Omron CX-Programmer project CJSCsp00 (CX-Programmer 3.01)

# PLC CJ_PC1: CJ1G-H CPU44

## Global symbols (name address type ; comment)
1509.11 BOOL  ; Sequence End
1509.15 BOOL  ; Busy of Macro
A202.00 BOOL  ; Ready of Logical Port0
A392.06 BOOL  ; Sys. Receive Complete
D100 CHANNEL  ; Axis Number
D101 CHANNEL  ; Function Code
D102 CHANNEL  ; Oｅｒａｎｄ L
D103 CHANNEL  ; Operand H
D105 CHANNEL  ; Stat. Res. Axis Number
D106 CHANNEL  ; PI PO
D107 CHANNEL  ; STAT ALRM
D120 CHANNEL  ; Pos. Res. Axis Number
D121 CHANNEL  ; Vel. Res. Axis Number
D122 CHANNEL  ; Read Res. Axis Number
D130 CHANNEL  ; Position L
D131 CHANNEL  ; Position H
D139 CHANNEL  ; Bytes ｔo Send
D159 CHANNEL  ; Bytes to Receive
D178 CHANNEL  ; Temp Register
D180 CHANNEL  ; Communication Parameter
D181 CHANNEL  ; 9600bps
D182 CHANNEL  ; Delay0
D184 CHANNEL  ; StartCode STX StopCode ETX
D185 CHANNEL  ; 14char/block
D188 CHANNEL  ; Half Duplex
D189 CHANNEL  ; Max Data Size
T0015 BOOL  ; Communicatin Idle Timer
W40.00 BOOL  ; Command Send Request
W40.01 BOOL  ; Communication is Executing
W40.02 BOOL  ; Res. Checksum Error
W40.05 BOOL  ; Responce Data OK
W40.07 BOOL  ; Command Send Req Pulse
W41.00 BOOL  ; Receive Complete
W41.01 BOOL  ; Sequence Normal End

## Program CJCSsp00 (cyclic task 0)

### Section ｾｸｼｮﾝ1

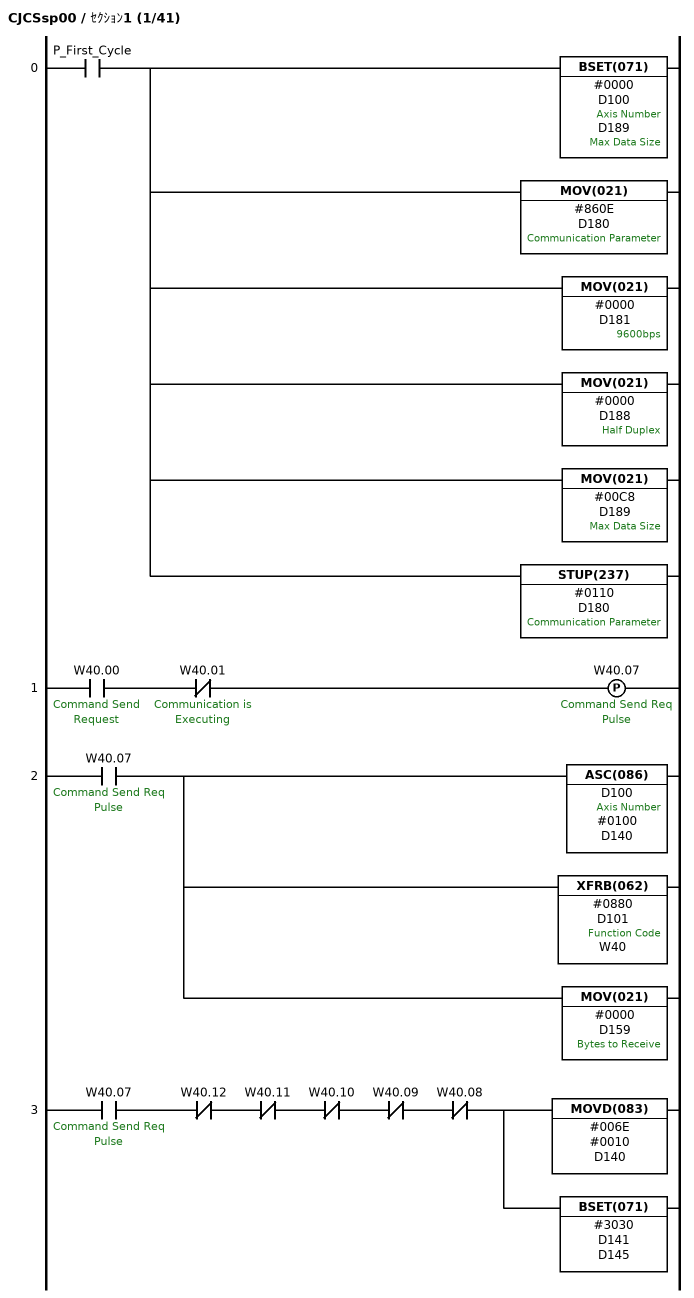
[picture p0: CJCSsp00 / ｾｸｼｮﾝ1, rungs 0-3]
; rung 0
LD P_First_Cycle
BSET(071) #0000 D100 D189  ; Axis Number, Max Data Size
MOV(021) #860E D180  ; Communication Parameter
MOV(021) #0000 D181  ; 9600bps
MOV(021) #0000 D188  ; Half Duplex
MOV(021) #00C8 D189  ; Max Data Size
STUP(237) #0110 D180  ; Communication Parameter
; rung 1
LD W40.00  ; Command Send Request
ANDNOT W40.01  ; Communication is Executing
DIFU(013) W40.07  ; Command Send Req Pulse
; rung 2
LD W40.07  ; Command Send Req Pulse
ASC(086) D100 #0100 D140  ; Axis Number
XFRB(062) #0880 D101 W40  ; Function Code
MOV(021) #0000 D159  ; Bytes to Receive
; rung 3
LD W40.07  ; Command Send Req Pulse
ANDNOT W40.12
ANDNOT W40.11
ANDNOT W40.10
ANDNOT W40.09
ANDNOT W40.08
MOVD(083) #006E #0010 D140
BSET(071) #3030 D141 D145

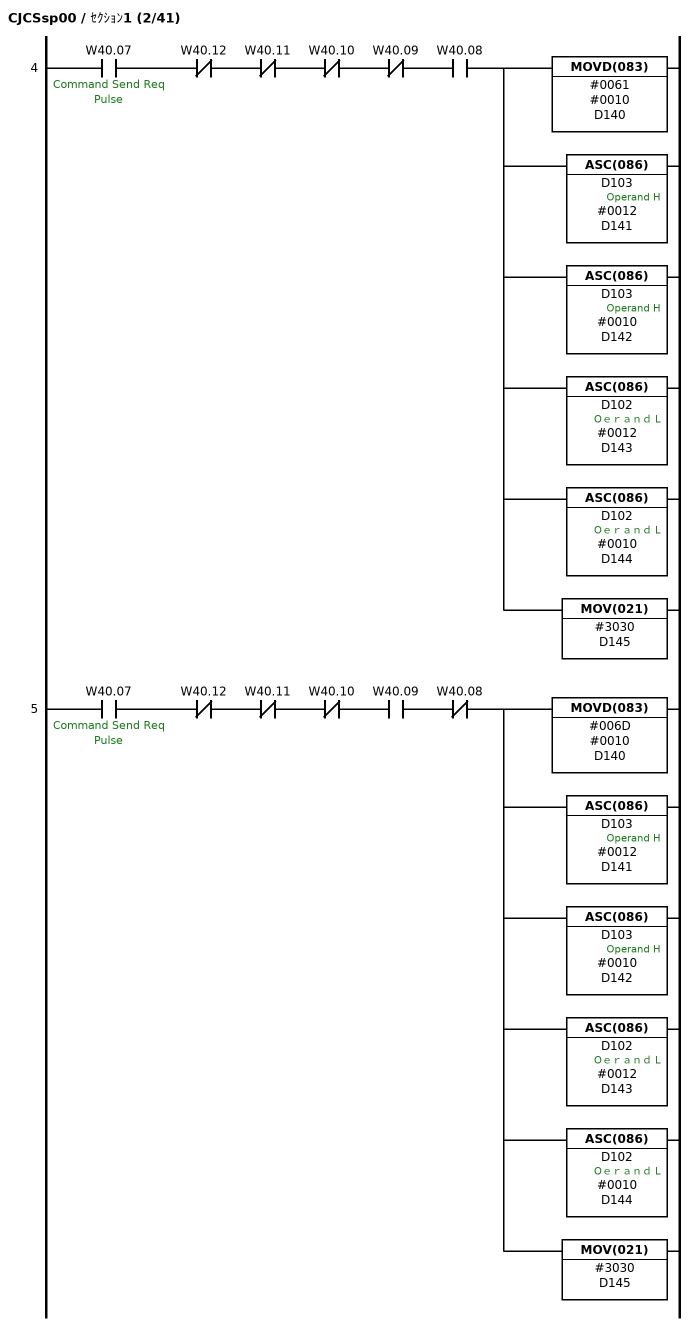
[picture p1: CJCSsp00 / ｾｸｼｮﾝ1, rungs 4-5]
; rung 4
LD W40.07  ; Command Send Req Pulse
ANDNOT W40.12
ANDNOT W40.11
ANDNOT W40.10
ANDNOT W40.09
AND W40.08
MOVD(083) #0061 #0010 D140
ASC(086) D103 #0012 D141  ; Operand H
ASC(086) D103 #0010 D142  ; Operand H
ASC(086) D102 #0012 D143  ; Oｅｒａｎｄ L
ASC(086) D102 #0010 D144  ; Oｅｒａｎｄ L
MOV(021) #3030 D145
; rung 5
LD W40.07  ; Command Send Req Pulse
ANDNOT W40.12
ANDNOT W40.11
ANDNOT W40.10
AND W40.09
ANDNOT W40.08
MOVD(083) #006D #0010 D140
ASC(086) D103 #0012 D141  ; Operand H
ASC(086) D103 #0010 D142  ; Operand H
ASC(086) D102 #0012 D143  ; Oｅｒａｎｄ L
ASC(086) D102 #0010 D144  ; Oｅｒａｎｄ L
MOV(021) #3030 D145

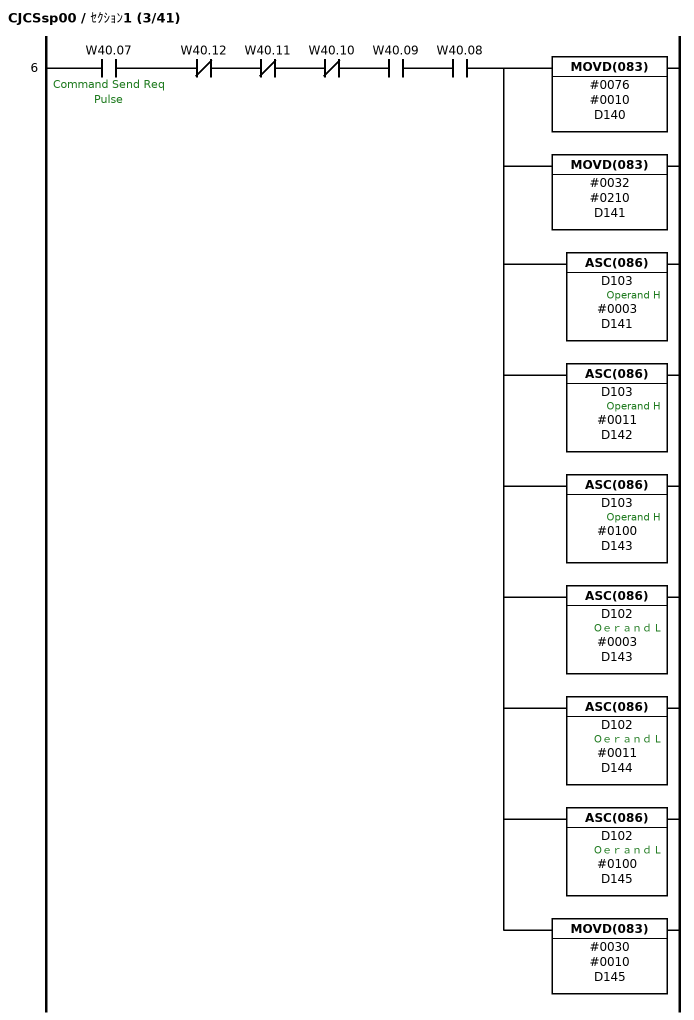
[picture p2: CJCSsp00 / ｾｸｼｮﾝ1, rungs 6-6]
; rung 6
LD W40.07  ; Command Send Req Pulse
ANDNOT W40.12
ANDNOT W40.11
ANDNOT W40.10
AND W40.09
AND W40.08
MOVD(083) #0076 #0010 D140
MOVD(083) #0032 #0210 D141
ASC(086) D103 #0003 D141  ; Operand H
ASC(086) D103 #0011 D142  ; Operand H
ASC(086) D103 #0100 D143  ; Operand H
ASC(086) D102 #0003 D143  ; Oｅｒａｎｄ L
ASC(086) D102 #0011 D144  ; Oｅｒａｎｄ L
ASC(086) D102 #0100 D145  ; Oｅｒａｎｄ L
MOVD(083) #0030 #0010 D145

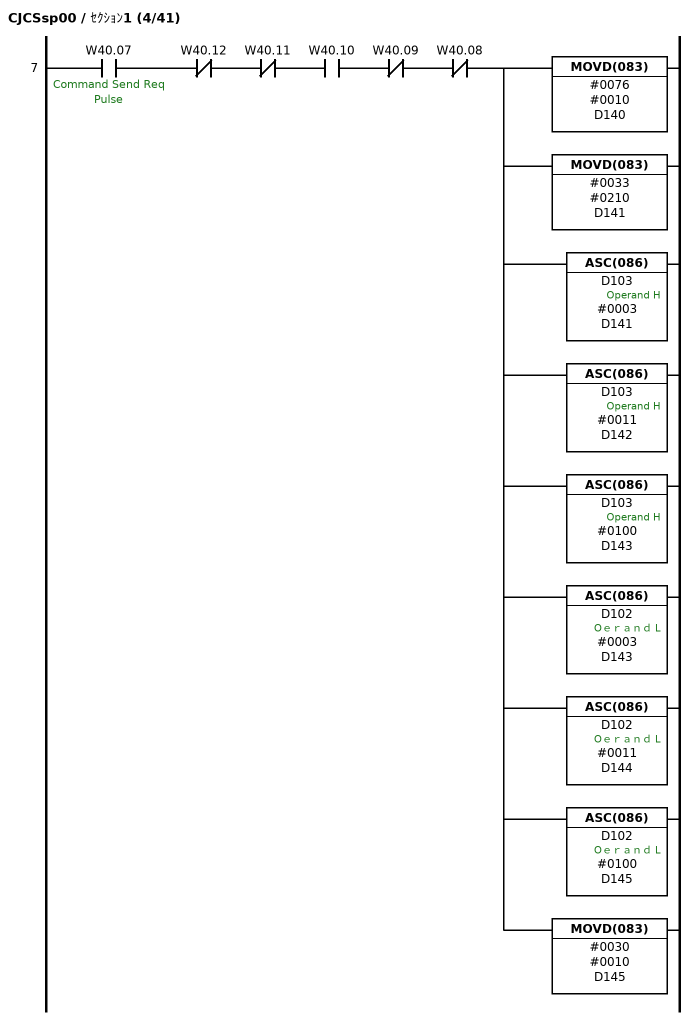
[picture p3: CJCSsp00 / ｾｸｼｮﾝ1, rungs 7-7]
; rung 7
LD W40.07  ; Command Send Req Pulse
ANDNOT W40.12
ANDNOT W40.11
AND W40.10
ANDNOT W40.09
ANDNOT W40.08
MOVD(083) #0076 #0010 D140
MOVD(083) #0033 #0210 D141
ASC(086) D103 #0003 D141  ; Operand H
ASC(086) D103 #0011 D142  ; Operand H
ASC(086) D103 #0100 D143  ; Operand H
ASC(086) D102 #0003 D143  ; Oｅｒａｎｄ L
ASC(086) D102 #0011 D144  ; Oｅｒａｎｄ L
ASC(086) D102 #0100 D145  ; Oｅｒａｎｄ L
MOVD(083) #0030 #0010 D145

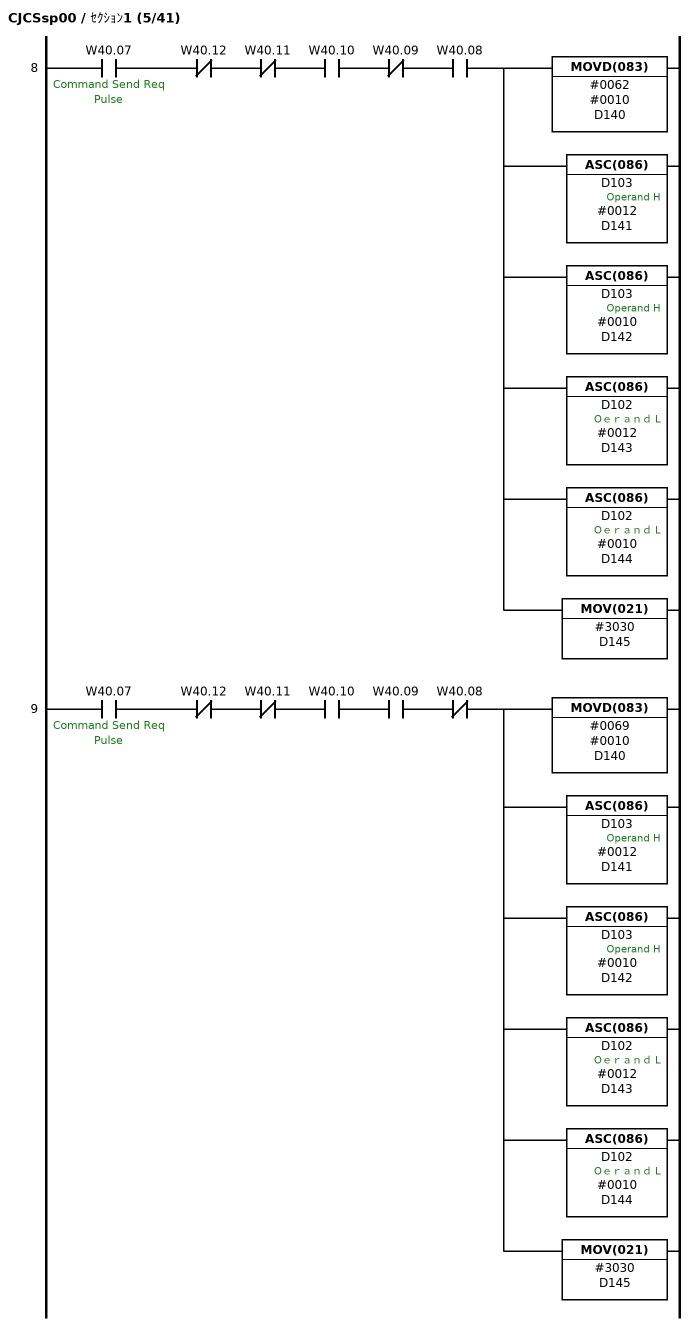
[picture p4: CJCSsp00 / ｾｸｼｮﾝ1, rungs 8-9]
; rung 8
LD W40.07  ; Command Send Req Pulse
ANDNOT W40.12
ANDNOT W40.11
AND W40.10
ANDNOT W40.09
AND W40.08
MOVD(083) #0062 #0010 D140
ASC(086) D103 #0012 D141  ; Operand H
ASC(086) D103 #0010 D142  ; Operand H
ASC(086) D102 #0012 D143  ; Oｅｒａｎｄ L
ASC(086) D102 #0010 D144  ; Oｅｒａｎｄ L
MOV(021) #3030 D145
; rung 9
LD W40.07  ; Command Send Req Pulse
ANDNOT W40.12
ANDNOT W40.11
AND W40.10
AND W40.09
ANDNOT W40.08
MOVD(083) #0069 #0010 D140
ASC(086) D103 #0012 D141  ; Operand H
ASC(086) D103 #0010 D142  ; Operand H
ASC(086) D102 #0012 D143  ; Oｅｒａｎｄ L
ASC(086) D102 #0010 D144  ; Oｅｒａｎｄ L
MOV(021) #3030 D145

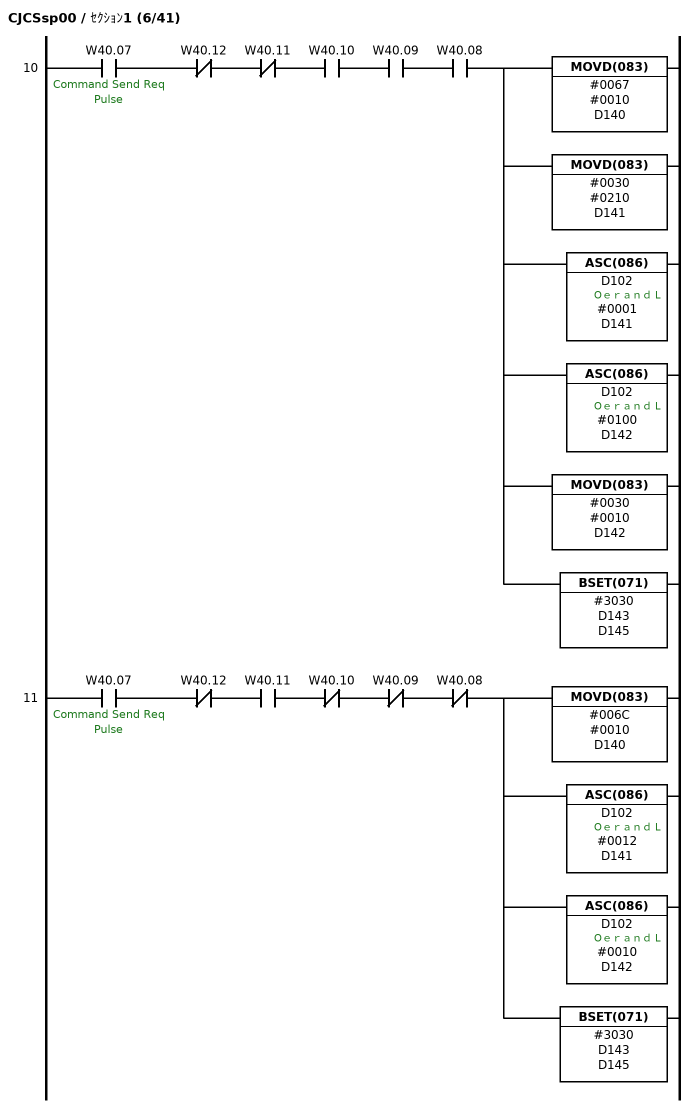
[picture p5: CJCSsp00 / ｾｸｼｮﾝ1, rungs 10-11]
; rung 10
LD W40.07  ; Command Send Req Pulse
ANDNOT W40.12
ANDNOT W40.11
AND W40.10
AND W40.09
AND W40.08
MOVD(083) #0067 #0010 D140
MOVD(083) #0030 #0210 D141
ASC(086) D102 #0001 D141  ; Oｅｒａｎｄ L
ASC(086) D102 #0100 D142  ; Oｅｒａｎｄ L
MOVD(083) #0030 #0010 D142
BSET(071) #3030 D143 D145
; rung 11
LD W40.07  ; Command Send Req Pulse
ANDNOT W40.12
AND W40.11
ANDNOT W40.10
ANDNOT W40.09
ANDNOT W40.08
MOVD(083) #006C #0010 D140
ASC(086) D102 #0012 D141  ; Oｅｒａｎｄ L
ASC(086) D102 #0010 D142  ; Oｅｒａｎｄ L
BSET(071) #3030 D143 D145

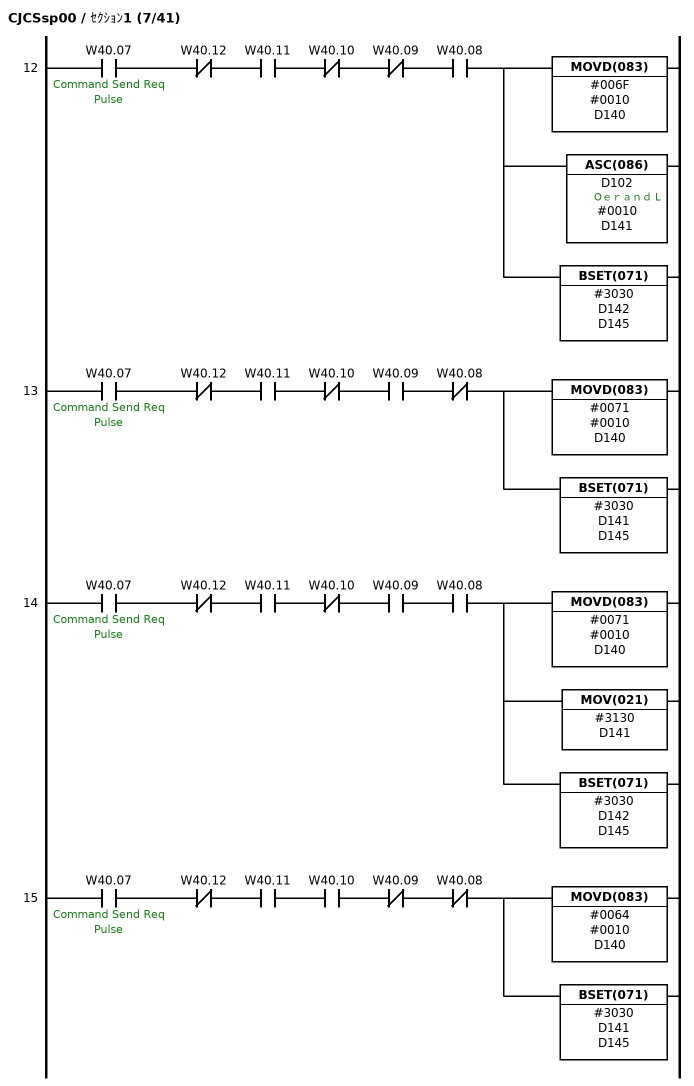
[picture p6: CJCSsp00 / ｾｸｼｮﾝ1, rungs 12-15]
; rung 12
LD W40.07  ; Command Send Req Pulse
ANDNOT W40.12
AND W40.11
ANDNOT W40.10
ANDNOT W40.09
AND W40.08
MOVD(083) #006F #0010 D140
ASC(086) D102 #0010 D141  ; Oｅｒａｎｄ L
BSET(071) #3030 D142 D145
; rung 13
LD W40.07  ; Command Send Req Pulse
ANDNOT W40.12
AND W40.11
ANDNOT W40.10
AND W40.09
ANDNOT W40.08
MOVD(083) #0071 #0010 D140
BSET(071) #3030 D141 D145
; rung 14
LD W40.07  ; Command Send Req Pulse
ANDNOT W40.12
AND W40.11
ANDNOT W40.10
AND W40.09
AND W40.08
MOVD(083) #0071 #0010 D140
MOV(021) #3130 D141
BSET(071) #3030 D142 D145
; rung 15
LD W40.07  ; Command Send Req Pulse
ANDNOT W40.12
AND W40.11
AND W40.10
ANDNOT W40.09
ANDNOT W40.08
MOVD(083) #0064 #0010 D140
BSET(071) #3030 D141 D145

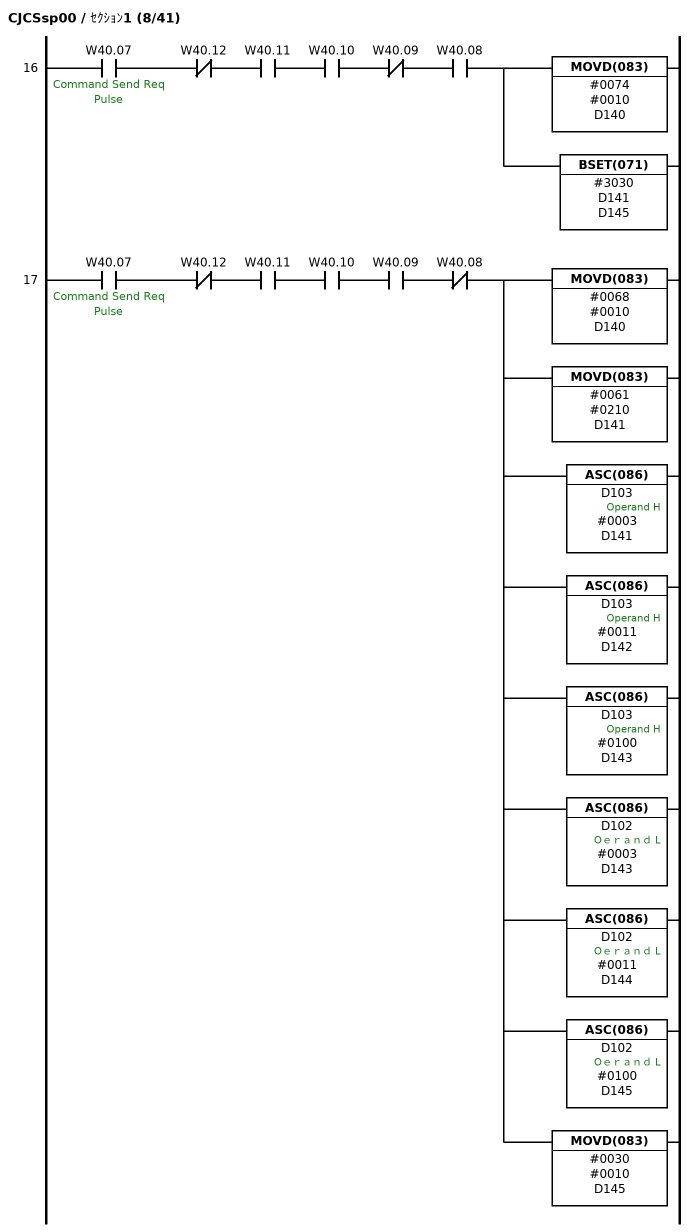
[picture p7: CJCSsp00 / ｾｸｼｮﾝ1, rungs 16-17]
; rung 16
LD W40.07  ; Command Send Req Pulse
ANDNOT W40.12
AND W40.11
AND W40.10
ANDNOT W40.09
AND W40.08
MOVD(083) #0074 #0010 D140
BSET(071) #3030 D141 D145
; rung 17
LD W40.07  ; Command Send Req Pulse
ANDNOT W40.12
AND W40.11
AND W40.10
AND W40.09
ANDNOT W40.08
MOVD(083) #0068 #0010 D140
MOVD(083) #0061 #0210 D141
ASC(086) D103 #0003 D141  ; Operand H
ASC(086) D103 #0011 D142  ; Operand H
ASC(086) D103 #0100 D143  ; Operand H
ASC(086) D102 #0003 D143  ; Oｅｒａｎｄ L
ASC(086) D102 #0011 D144  ; Oｅｒａｎｄ L
ASC(086) D102 #0100 D145  ; Oｅｒａｎｄ L
MOVD(083) #0030 #0010 D145

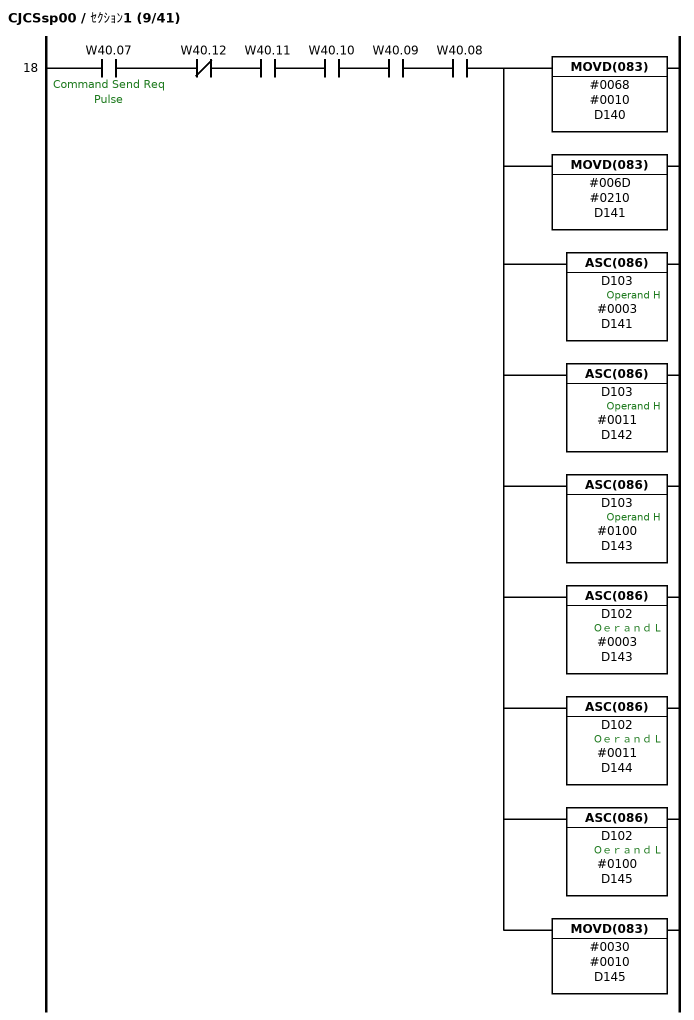
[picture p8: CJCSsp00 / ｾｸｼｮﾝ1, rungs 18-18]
; rung 18
LD W40.07  ; Command Send Req Pulse
ANDNOT W40.12
AND W40.11
AND W40.10
AND W40.09
AND W40.08
MOVD(083) #0068 #0010 D140
MOVD(083) #006D #0210 D141
ASC(086) D103 #0003 D141  ; Operand H
ASC(086) D103 #0011 D142  ; Operand H
ASC(086) D103 #0100 D143  ; Operand H
ASC(086) D102 #0003 D143  ; Oｅｒａｎｄ L
ASC(086) D102 #0011 D144  ; Oｅｒａｎｄ L
ASC(086) D102 #0100 D145  ; Oｅｒａｎｄ L
MOVD(083) #0030 #0010 D145

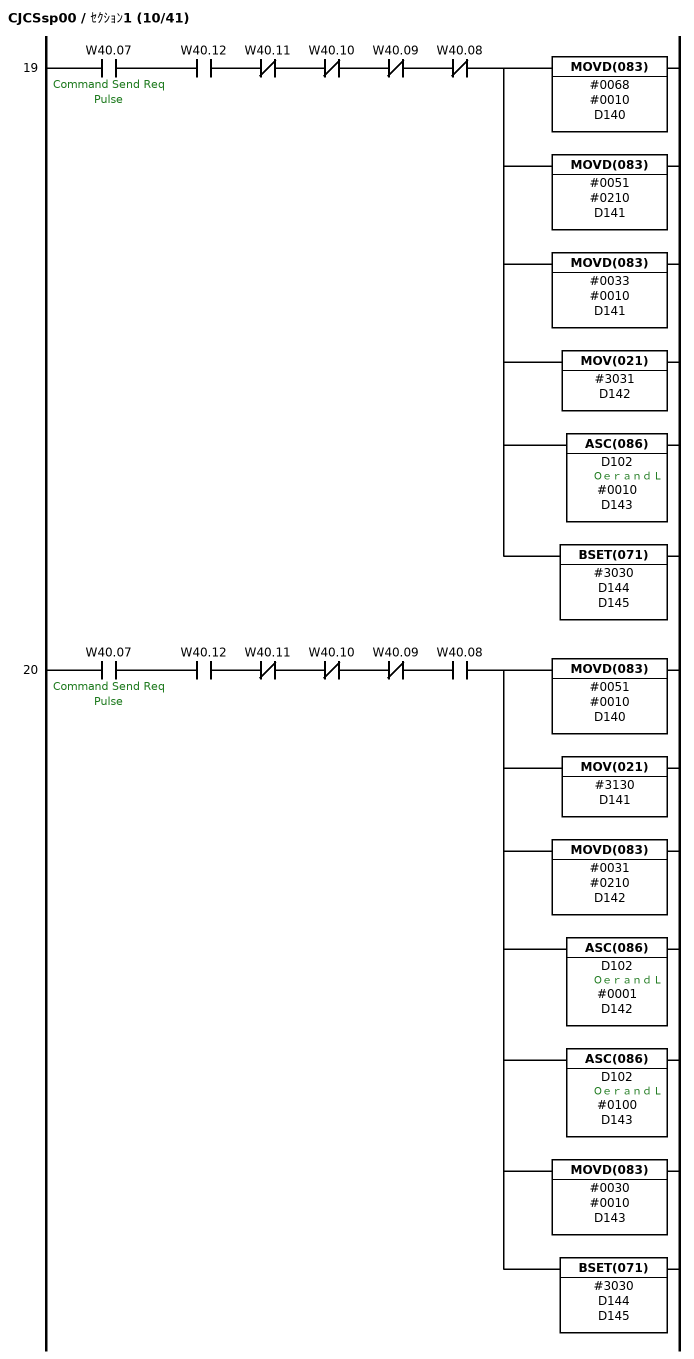
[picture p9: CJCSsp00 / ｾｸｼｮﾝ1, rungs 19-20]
; rung 19
LD W40.07  ; Command Send Req Pulse
AND W40.12
ANDNOT W40.11
ANDNOT W40.10
ANDNOT W40.09
ANDNOT W40.08
MOVD(083) #0068 #0010 D140
MOVD(083) #0051 #0210 D141
MOVD(083) #0033 #0010 D141
MOV(021) #3031 D142
ASC(086) D102 #0010 D143  ; Oｅｒａｎｄ L
BSET(071) #3030 D144 D145
; rung 20
LD W40.07  ; Command Send Req Pulse
AND W40.12
ANDNOT W40.11
ANDNOT W40.10
ANDNOT W40.09
AND W40.08
MOVD(083) #0051 #0010 D140
MOV(021) #3130 D141
MOVD(083) #0031 #0210 D142
ASC(086) D102 #0001 D142  ; Oｅｒａｎｄ L
ASC(086) D102 #0100 D143  ; Oｅｒａｎｄ L
MOVD(083) #0030 #0010 D143
BSET(071) #3030 D144 D145

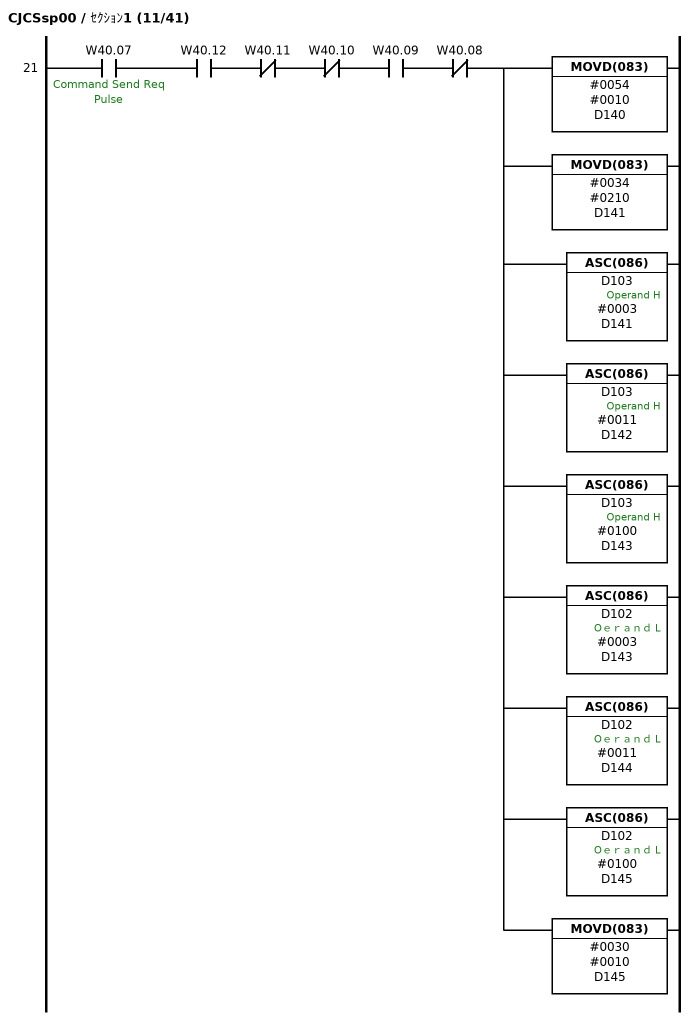
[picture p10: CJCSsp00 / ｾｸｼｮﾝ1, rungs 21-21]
; rung 21
LD W40.07  ; Command Send Req Pulse
AND W40.12
ANDNOT W40.11
ANDNOT W40.10
AND W40.09
ANDNOT W40.08
MOVD(083) #0054 #0010 D140
MOVD(083) #0034 #0210 D141
ASC(086) D103 #0003 D141  ; Operand H
ASC(086) D103 #0011 D142  ; Operand H
ASC(086) D103 #0100 D143  ; Operand H
ASC(086) D102 #0003 D143  ; Oｅｒａｎｄ L
ASC(086) D102 #0011 D144  ; Oｅｒａｎｄ L
ASC(086) D102 #0100 D145  ; Oｅｒａｎｄ L
MOVD(083) #0030 #0010 D145

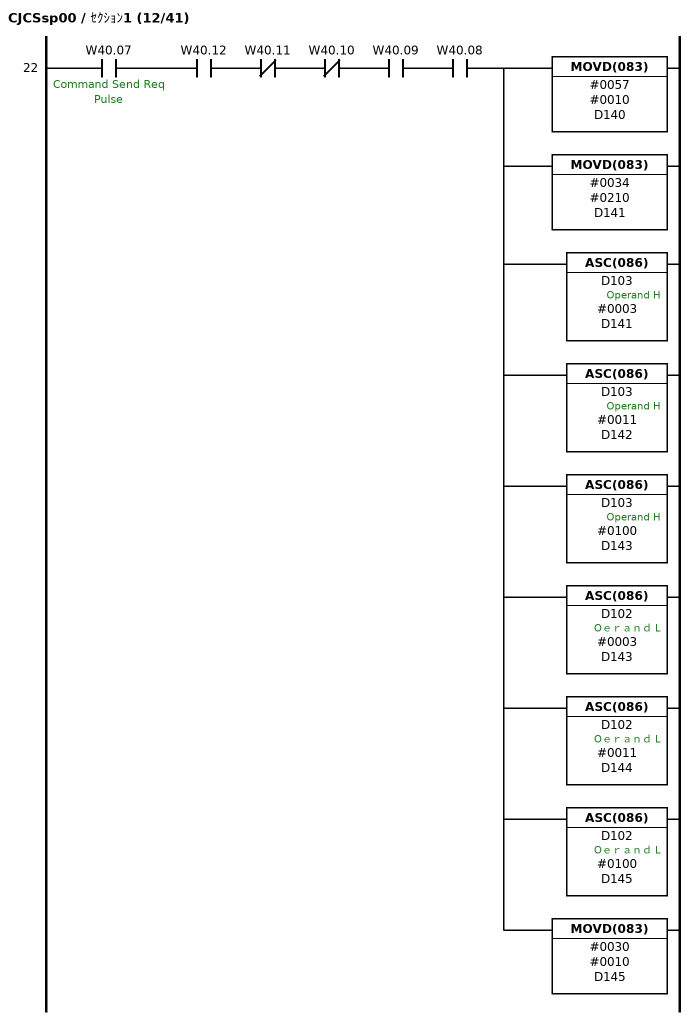
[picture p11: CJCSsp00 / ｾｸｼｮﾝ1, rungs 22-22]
; rung 22
LD W40.07  ; Command Send Req Pulse
AND W40.12
ANDNOT W40.11
ANDNOT W40.10
AND W40.09
AND W40.08
MOVD(083) #0057 #0010 D140
MOVD(083) #0034 #0210 D141
ASC(086) D103 #0003 D141  ; Operand H
ASC(086) D103 #0011 D142  ; Operand H
ASC(086) D103 #0100 D143  ; Operand H
ASC(086) D102 #0003 D143  ; Oｅｒａｎｄ L
ASC(086) D102 #0011 D144  ; Oｅｒａｎｄ L
ASC(086) D102 #0100 D145  ; Oｅｒａｎｄ L
MOVD(083) #0030 #0010 D145

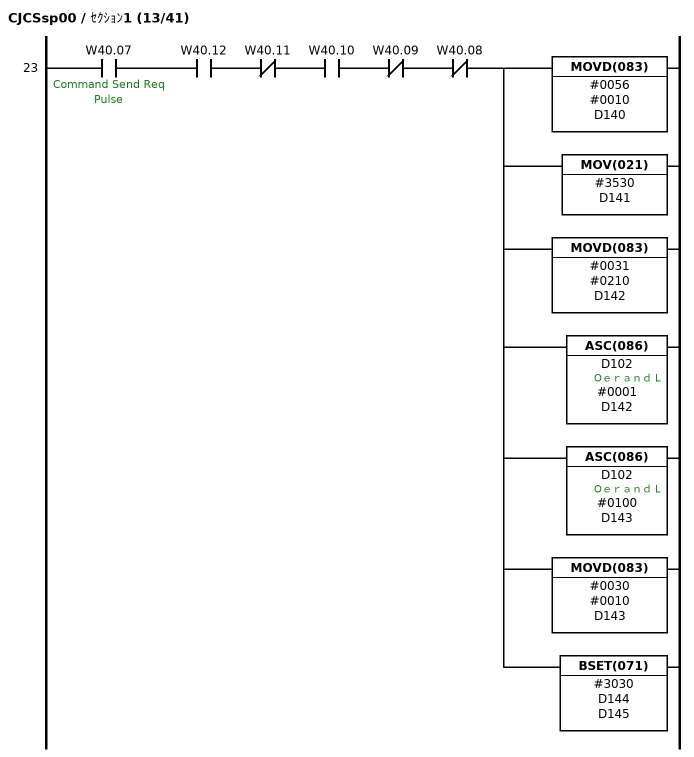
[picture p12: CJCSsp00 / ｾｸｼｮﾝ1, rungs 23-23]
; rung 23
LD W40.07  ; Command Send Req Pulse
AND W40.12
ANDNOT W40.11
AND W40.10
ANDNOT W40.09
ANDNOT W40.08
MOVD(083) #0056 #0010 D140
MOV(021) #3530 D141
MOVD(083) #0031 #0210 D142
ASC(086) D102 #0001 D142  ; Oｅｒａｎｄ L
ASC(086) D102 #0100 D143  ; Oｅｒａｎｄ L
MOVD(083) #0030 #0010 D143
BSET(071) #3030 D144 D145

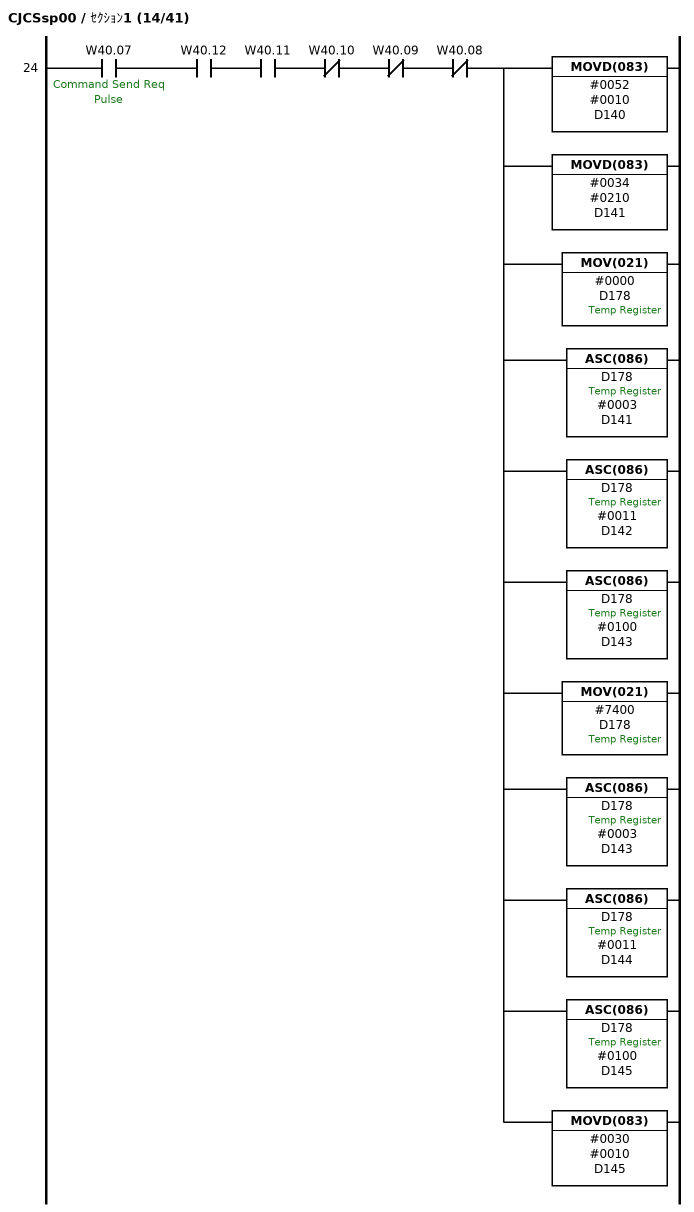
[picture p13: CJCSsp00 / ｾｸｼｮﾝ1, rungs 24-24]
; rung 24
LD W40.07  ; Command Send Req Pulse
AND W40.12
AND W40.11
ANDNOT W40.10
ANDNOT W40.09
ANDNOT W40.08
MOVD(083) #0052 #0010 D140
MOVD(083) #0034 #0210 D141
MOV(021) #0000 D178  ; Temp Register
ASC(086) D178 #0003 D141  ; Temp Register
ASC(086) D178 #0011 D142  ; Temp Register
ASC(086) D178 #0100 D143  ; Temp Register
MOV(021) #7400 D178  ; Temp Register
ASC(086) D178 #0003 D143  ; Temp Register
ASC(086) D178 #0011 D144  ; Temp Register
ASC(086) D178 #0100 D145  ; Temp Register
MOVD(083) #0030 #0010 D145

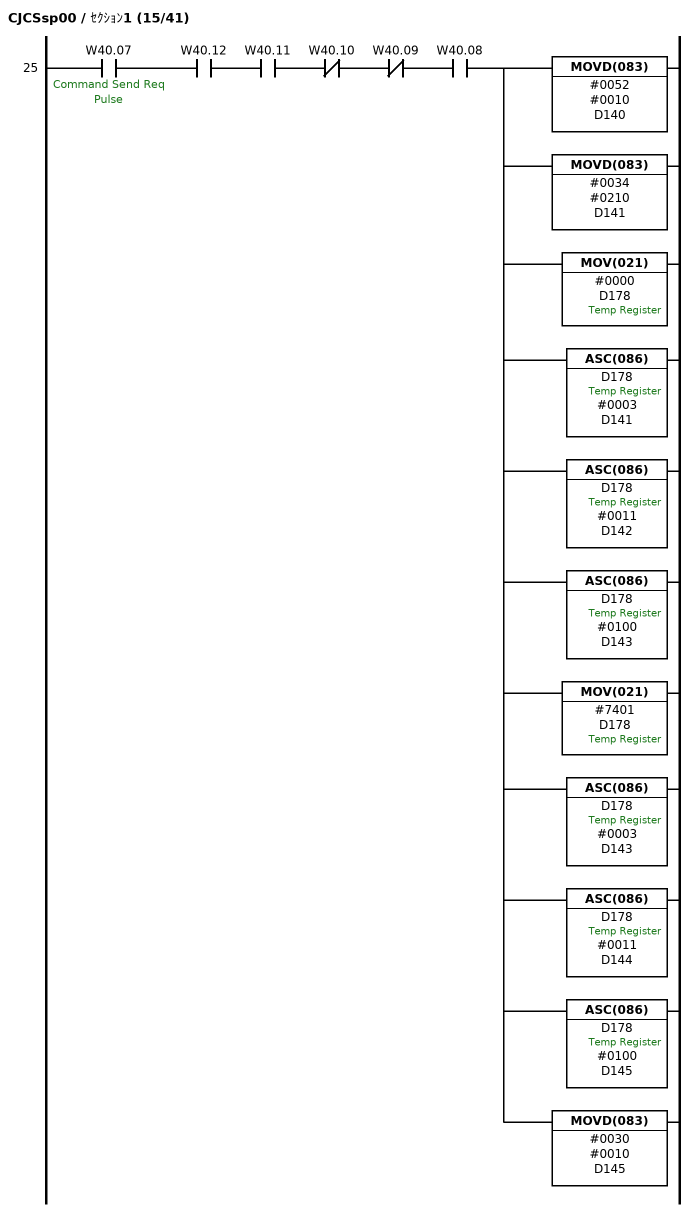
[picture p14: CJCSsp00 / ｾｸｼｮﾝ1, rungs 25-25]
; rung 25
LD W40.07  ; Command Send Req Pulse
AND W40.12
AND W40.11
ANDNOT W40.10
ANDNOT W40.09
AND W40.08
MOVD(083) #0052 #0010 D140
MOVD(083) #0034 #0210 D141
MOV(021) #0000 D178  ; Temp Register
ASC(086) D178 #0003 D141  ; Temp Register
ASC(086) D178 #0011 D142  ; Temp Register
ASC(086) D178 #0100 D143  ; Temp Register
MOV(021) #7401 D178  ; Temp Register
ASC(086) D178 #0003 D143  ; Temp Register
ASC(086) D178 #0011 D144  ; Temp Register
ASC(086) D178 #0100 D145  ; Temp Register
MOVD(083) #0030 #0010 D145

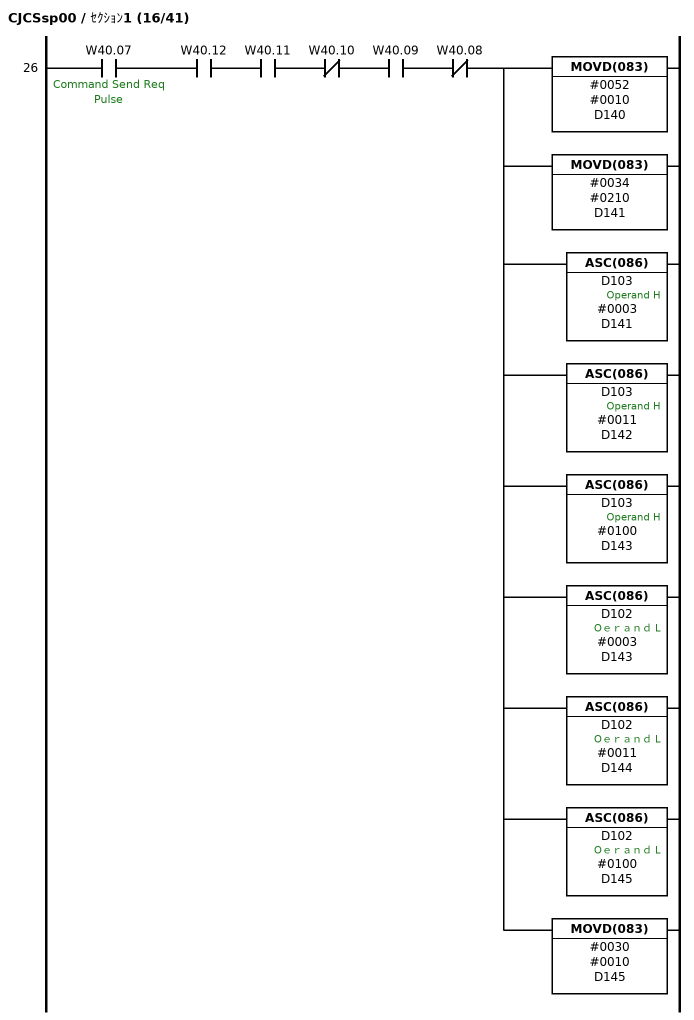
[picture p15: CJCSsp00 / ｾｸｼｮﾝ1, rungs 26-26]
; rung 26
LD W40.07  ; Command Send Req Pulse
AND W40.12
AND W40.11
ANDNOT W40.10
AND W40.09
ANDNOT W40.08
MOVD(083) #0052 #0010 D140
MOVD(083) #0034 #0210 D141
ASC(086) D103 #0003 D141  ; Operand H
ASC(086) D103 #0011 D142  ; Operand H
ASC(086) D103 #0100 D143  ; Operand H
ASC(086) D102 #0003 D143  ; Oｅｒａｎｄ L
ASC(086) D102 #0011 D144  ; Oｅｒａｎｄ L
ASC(086) D102 #0100 D145  ; Oｅｒａｎｄ L
MOVD(083) #0030 #0010 D145

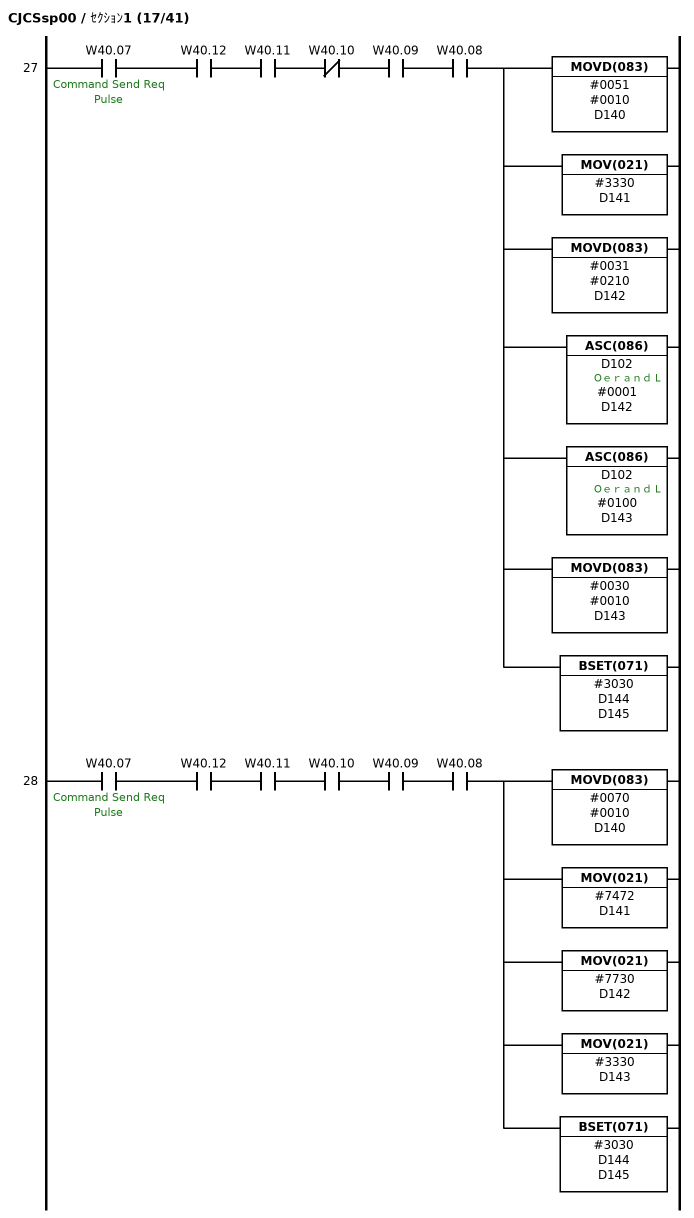
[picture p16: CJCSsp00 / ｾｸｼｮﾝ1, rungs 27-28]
; rung 27
LD W40.07  ; Command Send Req Pulse
AND W40.12
AND W40.11
ANDNOT W40.10
AND W40.09
AND W40.08
MOVD(083) #0051 #0010 D140
MOV(021) #3330 D141
MOVD(083) #0031 #0210 D142
ASC(086) D102 #0001 D142  ; Oｅｒａｎｄ L
ASC(086) D102 #0100 D143  ; Oｅｒａｎｄ L
MOVD(083) #0030 #0010 D143
BSET(071) #3030 D144 D145
; rung 28
LD W40.07  ; Command Send Req Pulse
AND W40.12
AND W40.11
AND W40.10
AND W40.09
AND W40.08
MOVD(083) #0070 #0010 D140
MOV(021) #7472 D141
MOV(021) #7730 D142
MOV(021) #3330 D143
BSET(071) #3030 D144 D145

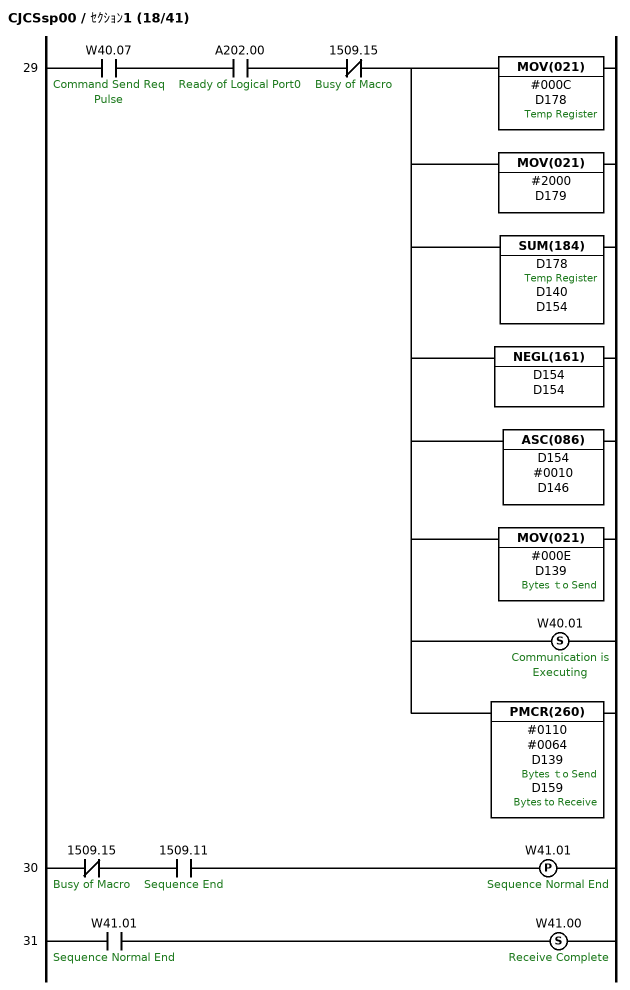
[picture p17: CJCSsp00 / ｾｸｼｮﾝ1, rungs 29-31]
; rung 29
LD W40.07  ; Command Send Req Pulse
AND A202.00  ; Ready of Logical Port0
ANDNOT 1509.15  ; Busy of Macro
MOV(021) #000C D178  ; Temp Register
MOV(021) #2000 D179
SUM(184) D178 D140 D154  ; Temp Register
NEGL(161) D154 D154
ASC(086) D154 #0010 D146
MOV(021) #000E D139  ; Bytes ｔo Send
SET W40.01  ; Communication is Executing
PMCR(260) #0110 #0064 D139 D159  ; Bytes ｔo Send, Bytes to Receive
; rung 30
LDNOT 1509.15  ; Busy of Macro
AND 1509.11  ; Sequence End
DIFU(013) W41.01  ; Sequence Normal End
; rung 31
LD W41.01  ; Sequence Normal End
SET W41.00  ; Receive Complete

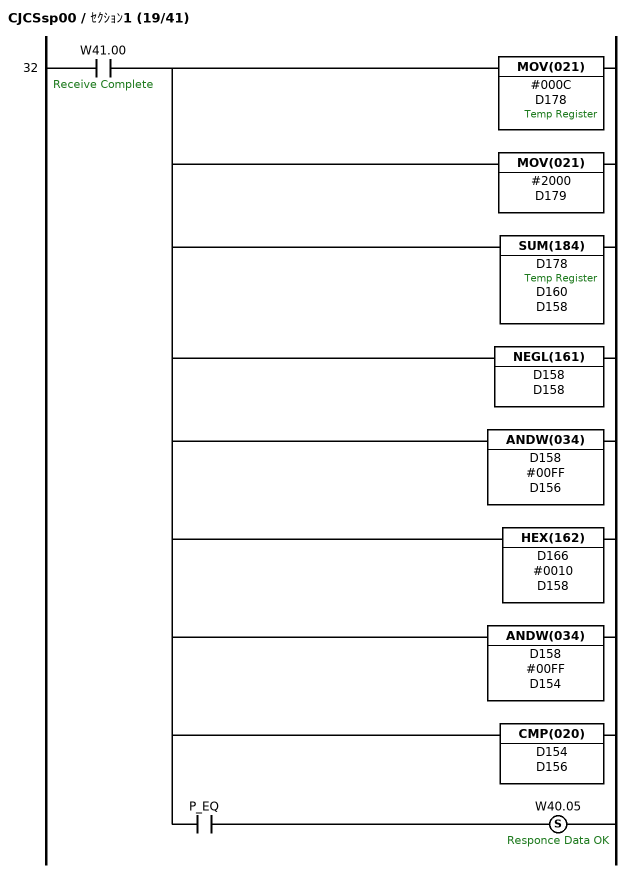
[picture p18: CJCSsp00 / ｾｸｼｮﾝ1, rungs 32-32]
; rung 32
LD W41.00  ; Receive Complete
MOV(021) #000C D178  ; Temp Register
MOV(021) #2000 D179
SUM(184) D178 D160 D158  ; Temp Register
NEGL(161) D158 D158
ANDW(034) D158 #00FF D156
HEX(162) D166 #0010 D158
ANDW(034) D158 #00FF D154
CMP(020) D154 D156
AND P_EQ
SET W40.05  ; Responce Data OK

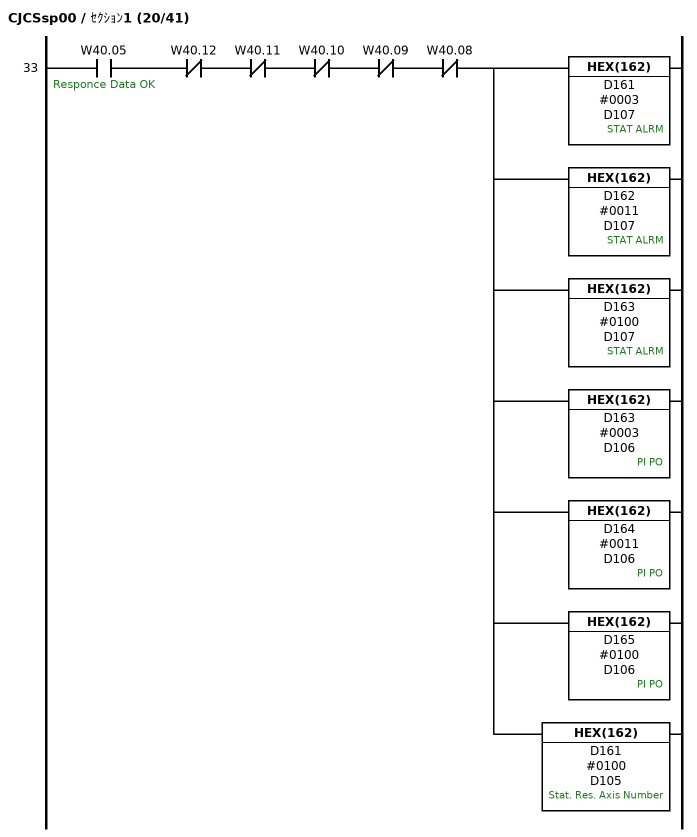
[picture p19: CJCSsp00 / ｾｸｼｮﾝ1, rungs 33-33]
; rung 33
LD W40.05  ; Responce Data OK
ANDNOT W40.12
ANDNOT W40.11
ANDNOT W40.10
ANDNOT W40.09
ANDNOT W40.08
HEX(162) D161 #0003 D107  ; STAT ALRM
HEX(162) D162 #0011 D107  ; STAT ALRM
HEX(162) D163 #0100 D107  ; STAT ALRM
HEX(162) D163 #0003 D106  ; PI PO
HEX(162) D164 #0011 D106  ; PI PO
HEX(162) D165 #0100 D106  ; PI PO
HEX(162) D161 #0100 D105  ; Stat. Res. Axis Number

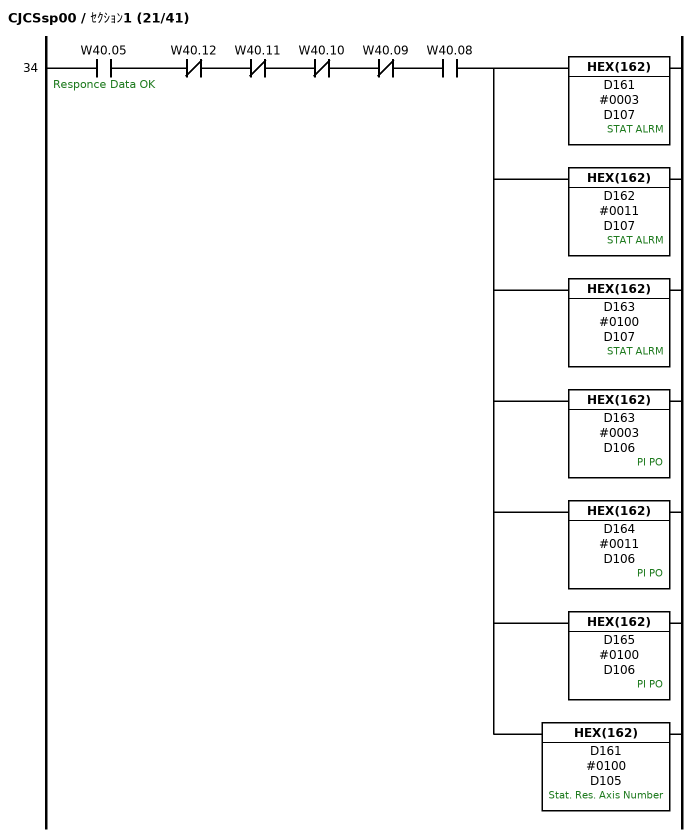
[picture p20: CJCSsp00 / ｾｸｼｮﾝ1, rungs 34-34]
; rung 34
LD W40.05  ; Responce Data OK
ANDNOT W40.12
ANDNOT W40.11
ANDNOT W40.10
ANDNOT W40.09
AND W40.08
HEX(162) D161 #0003 D107  ; STAT ALRM
HEX(162) D162 #0011 D107  ; STAT ALRM
HEX(162) D163 #0100 D107  ; STAT ALRM
HEX(162) D163 #0003 D106  ; PI PO
HEX(162) D164 #0011 D106  ; PI PO
HEX(162) D165 #0100 D106  ; PI PO
HEX(162) D161 #0100 D105  ; Stat. Res. Axis Number

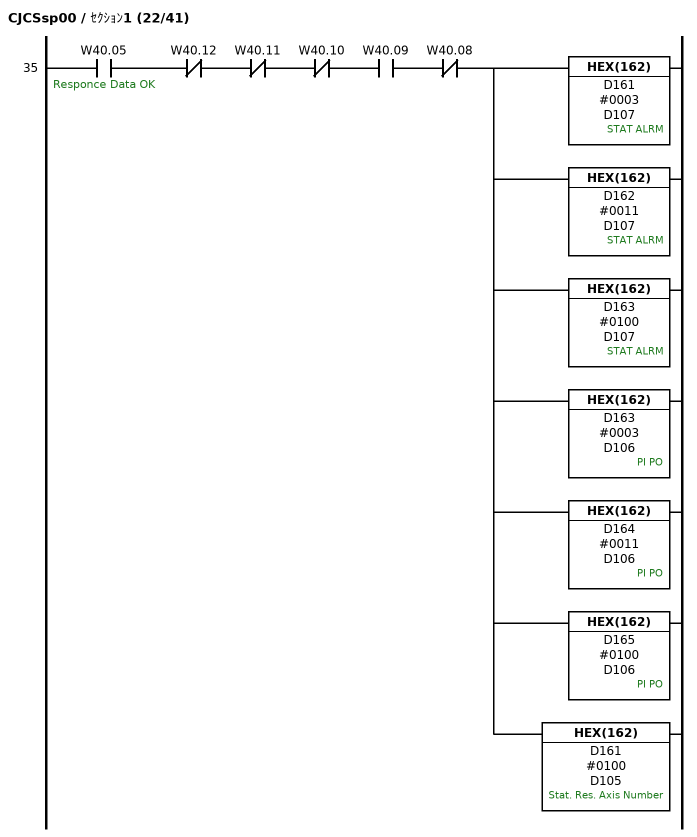
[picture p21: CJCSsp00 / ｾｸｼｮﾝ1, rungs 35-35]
; rung 35
LD W40.05  ; Responce Data OK
ANDNOT W40.12
ANDNOT W40.11
ANDNOT W40.10
AND W40.09
ANDNOT W40.08
HEX(162) D161 #0003 D107  ; STAT ALRM
HEX(162) D162 #0011 D107  ; STAT ALRM
HEX(162) D163 #0100 D107  ; STAT ALRM
HEX(162) D163 #0003 D106  ; PI PO
HEX(162) D164 #0011 D106  ; PI PO
HEX(162) D165 #0100 D106  ; PI PO
HEX(162) D161 #0100 D105  ; Stat. Res. Axis Number

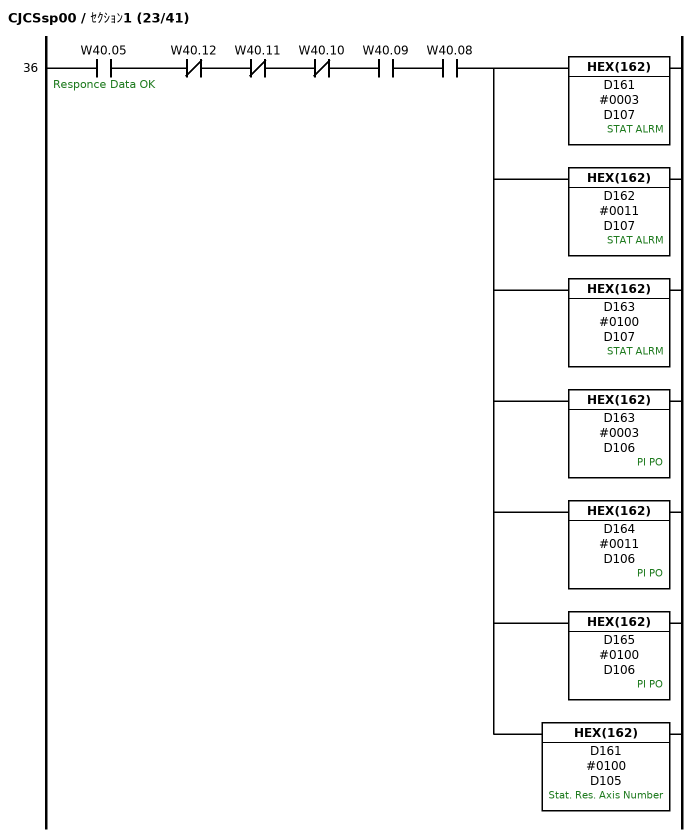
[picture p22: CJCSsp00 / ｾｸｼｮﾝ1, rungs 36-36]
; rung 36
LD W40.05  ; Responce Data OK
ANDNOT W40.12
ANDNOT W40.11
ANDNOT W40.10
AND W40.09
AND W40.08
HEX(162) D161 #0003 D107  ; STAT ALRM
HEX(162) D162 #0011 D107  ; STAT ALRM
HEX(162) D163 #0100 D107  ; STAT ALRM
HEX(162) D163 #0003 D106  ; PI PO
HEX(162) D164 #0011 D106  ; PI PO
HEX(162) D165 #0100 D106  ; PI PO
HEX(162) D161 #0100 D105  ; Stat. Res. Axis Number

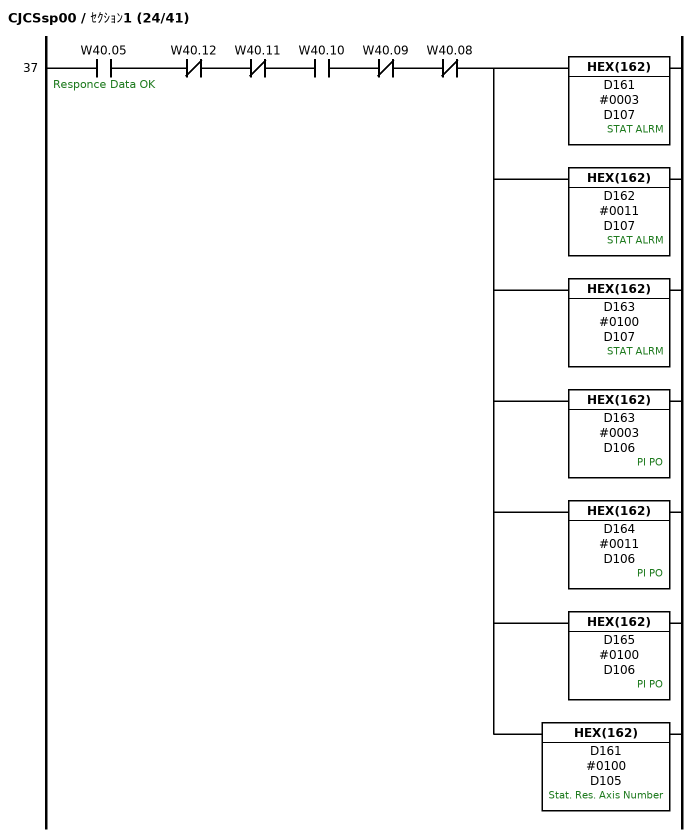
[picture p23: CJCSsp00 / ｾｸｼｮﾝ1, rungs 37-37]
; rung 37
LD W40.05  ; Responce Data OK
ANDNOT W40.12
ANDNOT W40.11
AND W40.10
ANDNOT W40.09
ANDNOT W40.08
HEX(162) D161 #0003 D107  ; STAT ALRM
HEX(162) D162 #0011 D107  ; STAT ALRM
HEX(162) D163 #0100 D107  ; STAT ALRM
HEX(162) D163 #0003 D106  ; PI PO
HEX(162) D164 #0011 D106  ; PI PO
HEX(162) D165 #0100 D106  ; PI PO
HEX(162) D161 #0100 D105  ; Stat. Res. Axis Number

; rung 38
LD W40.05  ; Responce Data OK
ANDNOT W40.12
ANDNOT W40.11
AND W40.10
ANDNOT W40.09
AND W40.08
HEX(162) D161 #0003 D107  ; STAT ALRM
HEX(162) D162 #0011 D107  ; STAT ALRM
HEX(162) D163 #0100 D107  ; STAT ALRM
HEX(162) D163 #0003 D106  ; PI PO
HEX(162) D164 #0011 D106  ; PI PO
HEX(162) D165 #0100 D106  ; PI PO
HEX(162) D161 #0100 D105  ; Stat. Res. Axis Number

; rung 39
LD W40.05  ; Responce Data OK
ANDNOT W40.12
ANDNOT W40.11
AND W40.10
AND W40.09
ANDNOT W40.08
HEX(162) D161 #0003 D107  ; STAT ALRM
HEX(162) D162 #0011 D107  ; STAT ALRM
HEX(162) D163 #0100 D107  ; STAT ALRM
HEX(162) D163 #0003 D106  ; PI PO
HEX(162) D164 #0011 D106  ; PI PO
HEX(162) D165 #0100 D106  ; PI PO
HEX(162) D161 #0100 D105  ; Stat. Res. Axis Number

; rung 40
LD W40.05  ; Responce Data OK
ANDNOT W40.12
ANDNOT W40.11
AND W40.10
AND W40.09
AND W40.08
HEX(162) D161 #0003 D107  ; STAT ALRM
HEX(162) D162 #0011 D107  ; STAT ALRM
HEX(162) D163 #0100 D107  ; STAT ALRM
HEX(162) D163 #0003 D106  ; PI PO
HEX(162) D164 #0011 D106  ; PI PO
HEX(162) D165 #0100 D106  ; PI PO
HEX(162) D161 #0100 D105  ; Stat. Res. Axis Number

; rung 41
LD W40.05  ; Responce Data OK
ANDNOT W40.12
AND W40.11
ANDNOT W40.10
ANDNOT W40.09
ANDNOT W40.08
HEX(162) D161 #0003 D107  ; STAT ALRM
HEX(162) D162 #0011 D107  ; STAT ALRM
HEX(162) D163 #0100 D107  ; STAT ALRM
HEX(162) D163 #0003 D106  ; PI PO
HEX(162) D164 #0011 D106  ; PI PO
HEX(162) D165 #0100 D106  ; PI PO
HEX(162) D161 #0100 D105  ; Stat. Res. Axis Number

; rung 42
LD W40.05  ; Responce Data OK
ANDNOT W40.12
AND W40.11
ANDNOT W40.10
ANDNOT W40.09
AND W40.08
HEX(162) D161 #0003 D107  ; STAT ALRM
HEX(162) D162 #0011 D107  ; STAT ALRM
HEX(162) D163 #0100 D107  ; STAT ALRM
HEX(162) D163 #0003 D106  ; PI PO
HEX(162) D164 #0011 D106  ; PI PO
HEX(162) D165 #0100 D106  ; PI PO
HEX(162) D161 #0100 D105  ; Stat. Res. Axis Number

; rung 43
LD W40.05  ; Responce Data OK
ANDNOT W40.12
AND W40.11
ANDNOT W40.10
AND W40.09
ANDNOT W40.08
HEX(162) D161 #0003 D107  ; STAT ALRM
HEX(162) D162 #0011 D107  ; STAT ALRM
HEX(162) D163 #0100 D107  ; STAT ALRM
HEX(162) D163 #0003 D106  ; PI PO
HEX(162) D164 #0011 D106  ; PI PO
HEX(162) D165 #0100 D106  ; PI PO
HEX(162) D161 #0100 D105  ; Stat. Res. Axis Number

; rung 44
LD W40.05  ; Responce Data OK
ANDNOT W40.12
AND W40.11
ANDNOT W40.10
AND W40.09
AND W40.08
HEX(162) D161 #0003 D107  ; STAT ALRM
HEX(162) D162 #0011 D107  ; STAT ALRM
HEX(162) D163 #0100 D107  ; STAT ALRM
HEX(162) D163 #0003 D106  ; PI PO
HEX(162) D164 #0011 D106  ; PI PO
HEX(162) D165 #0100 D106  ; PI PO
HEX(162) D161 #0100 D105  ; Stat. Res. Axis Number

; rung 45
LD W40.05  ; Responce Data OK
ANDNOT W40.12
AND W40.11
AND W40.10
ANDNOT W40.09
ANDNOT W40.08
HEX(162) D161 #0003 D107  ; STAT ALRM
HEX(162) D162 #0011 D107  ; STAT ALRM
HEX(162) D163 #0100 D107  ; STAT ALRM
HEX(162) D163 #0003 D106  ; PI PO
HEX(162) D164 #0011 D106  ; PI PO
HEX(162) D165 #0100 D106  ; PI PO
HEX(162) D161 #0100 D105  ; Stat. Res. Axis Number

; rung 46
LD W40.05  ; Responce Data OK
ANDNOT W40.12
AND W40.11
AND W40.10
ANDNOT W40.09
AND W40.08
HEX(162) D161 #0003 D107  ; STAT ALRM
HEX(162) D162 #0011 D107  ; STAT ALRM
HEX(162) D163 #0100 D107  ; STAT ALRM
HEX(162) D163 #0003 D106  ; PI PO
HEX(162) D164 #0011 D106  ; PI PO
HEX(162) D165 #0100 D106  ; PI PO
HEX(162) D161 #0100 D105  ; Stat. Res. Axis Number

; rung 47
LD W40.05  ; Responce Data OK
ANDNOT W40.12
AND W40.11
AND W40.10
AND W40.09
ANDNOT W40.08
HEX(162) D161 #0003 D107  ; STAT ALRM
HEX(162) D162 #0011 D107  ; STAT ALRM
HEX(162) D163 #0100 D107  ; STAT ALRM
HEX(162) D163 #0003 D106  ; PI PO
HEX(162) D164 #0011 D106  ; PI PO
HEX(162) D165 #0100 D106  ; PI PO
HEX(162) D161 #0100 D105  ; Stat. Res. Axis Number

; rung 48
LD W40.05  ; Responce Data OK
ANDNOT W40.12
AND W40.11
AND W40.10
AND W40.09
AND W40.08
HEX(162) D161 #0003 D107  ; STAT ALRM
HEX(162) D162 #0011 D107  ; STAT ALRM
HEX(162) D163 #0100 D107  ; STAT ALRM
HEX(162) D163 #0003 D106  ; PI PO
HEX(162) D164 #0011 D106  ; PI PO
HEX(162) D165 #0100 D106  ; PI PO
HEX(162) D161 #0100 D105  ; Stat. Res. Axis Number

; rung 49
LD W40.05  ; Responce Data OK
AND W40.12
ANDNOT W40.11
ANDNOT W40.10
ANDNOT W40.09
ANDNOT W40.08
HEX(162) D161 #0003 D107  ; STAT ALRM
HEX(162) D162 #0011 D107  ; STAT ALRM
HEX(162) D163 #0100 D107  ; STAT ALRM
HEX(162) D163 #0003 D106  ; PI PO
HEX(162) D164 #0011 D106  ; PI PO
HEX(162) D165 #0100 D106  ; PI PO
HEX(162) D161 #0100 D105  ; Stat. Res. Axis Number

; rung 50
LD W40.05  ; Responce Data OK
AND W40.12
ANDNOT W40.11
ANDNOT W40.10
ANDNOT W40.09
AND W40.08
HEX(162) D161 #0003 D107  ; STAT ALRM
HEX(162) D162 #0011 D107  ; STAT ALRM
HEX(162) D163 #0100 D107  ; STAT ALRM
HEX(162) D163 #0003 D106  ; PI PO
HEX(162) D164 #0011 D106  ; PI PO
HEX(162) D165 #0100 D106  ; PI PO
HEX(162) D161 #0100 D105  ; Stat. Res. Axis Number
; rung 51
LD W40.05  ; Responce Data OK
AND W40.12
ANDNOT W40.11
ANDNOT W40.10
AND W40.09
ANDNOT W40.08
HEX(162) D162 #0012 D137
HEX(162) D163 #0010 D137
HEX(162) D164 #0012 D136
HEX(162) D165 #0010 D136
HEX(162) D161 #0100 D105  ; Stat. Res. Axis Number

; rung 52
LD W40.05  ; Responce Data OK
AND W40.12
ANDNOT W40.11
ANDNOT W40.10
AND W40.09
AND W40.08
HEX(162) D162 #0012 D137
HEX(162) D163 #0010 D137
HEX(162) D164 #0012 D136
HEX(162) D165 #0010 D136
HEX(162) D161 #0100 D105  ; Stat. Res. Axis Number
; rung 53
LD W40.05  ; Responce Data OK
AND W40.12
ANDNOT W40.11
AND W40.10
ANDNOT W40.09
ANDNOT W40.08
HEX(162) D162 #0012 D139  ; Bytes ｔo Send
HEX(162) D163 #0010 D139  ; Bytes ｔo Send
HEX(162) D164 #0012 D138
HEX(162) D165 #0010 D138
HEX(162) D161 #0100 D105  ; Stat. Res. Axis Number

; rung 54
LD W40.05  ; Responce Data OK
AND W40.12
AND W40.11
ANDNOT W40.10
ANDNOT W40.09
ANDNOT W40.08
HEX(162) D162 #0012 D131  ; Position H
HEX(162) D163 #0010 D131  ; Position H
HEX(162) D164 #0012 D130  ; Position L
HEX(162) D165 #0010 D130  ; Position L
HEX(162) D161 #0100 D120  ; Pos. Res. Axis Number
; rung 55
LD W40.05  ; Responce Data OK
AND W40.12
AND W40.11
ANDNOT W40.10
ANDNOT W40.09
AND W40.08
HEX(162) D162 #0012 D133
HEX(162) D163 #0010 D133
HEX(162) D164 #0012 D132
HEX(162) D165 #0010 D132
HEX(162) D161 #0100 D121  ; Vel. Res. Axis Number

; rung 56
LD W40.05  ; Responce Data OK
AND W40.12
AND W40.11
ANDNOT W40.10
AND W40.09
ANDNOT W40.08
HEX(162) D162 #0012 D135
HEX(162) D163 #0010 D135
HEX(162) D164 #0012 D134
HEX(162) D165 #0010 D134
HEX(162) D161 #0100 D122  ; Read Res. Axis Number
; rung 57
LD W40.05  ; Responce Data OK
AND W40.12
AND W40.11
ANDNOT W40.10
AND W40.09
AND W40.08
HEX(162) D161 #0003 D107  ; STAT ALRM
HEX(162) D162 #0011 D107  ; STAT ALRM
HEX(162) D163 #0100 D107  ; STAT ALRM
HEX(162) D163 #0003 D106  ; PI PO
HEX(162) D164 #0011 D106  ; PI PO
HEX(162) D165 #0100 D106  ; PI PO
HEX(162) D161 #0100 D105  ; Stat. Res. Axis Number

; rung 58
LD W40.05  ; Responce Data OK
AND W40.12
AND W40.11
AND W40.10
AND W40.09
AND W40.08
HEX(162) D161 #0003 D107  ; STAT ALRM
HEX(162) D162 #0011 D107  ; STAT ALRM
HEX(162) D163 #0100 D107  ; STAT ALRM
HEX(162) D163 #0003 D106  ; PI PO
HEX(162) D164 #0011 D106  ; PI PO
HEX(162) D165 #0100 D106  ; PI PO
HEX(162) D161 #0100 D105  ; Stat. Res. Axis Number
; rung 59
LD W41.00  ; Receive Complete
TMHH(540) 0015 #0003  ; Communicatin Idle Timer
; rung 60
LD T0015  ; Communicatin Idle Timer
OUT TR0
RSET W40.01  ; Communication is Executing
ANDNOT W40.05  ; Responce Data OK
SET W40.02  ; Res. Checksum Error
LD TR0
AND W40.05  ; Responce Data OK
RSET W40.02  ; Res. Checksum Error
LD TR0
RSET W40.05  ; Responce Data OK
RSET W41.00  ; Receive Complete
; rung 61
END(001)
